One B-rep face of a CAD part: STEP entity #1838.
In plain terms, the planar face has unit normal (1, 0, 0).
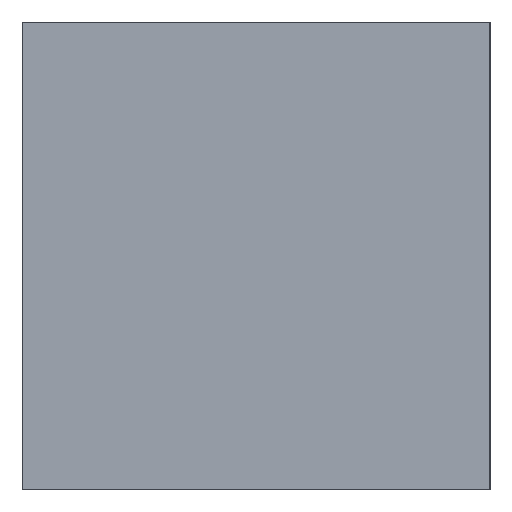
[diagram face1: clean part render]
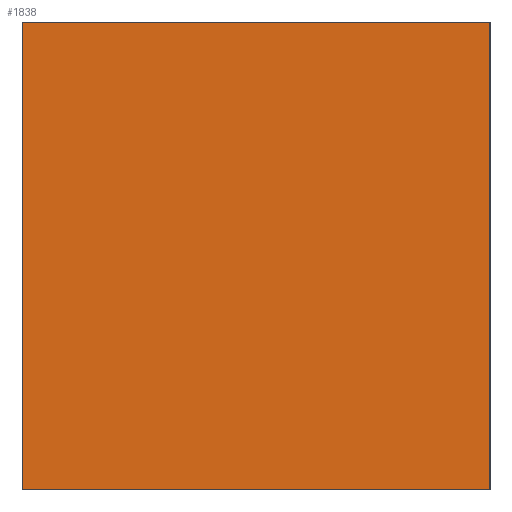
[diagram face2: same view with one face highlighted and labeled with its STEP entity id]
Its self-contained STEP definition (entity closure, numbers rounded to 3 decimals):
#1799=CARTESIAN_POINT('Axis2P3D Location',(-150.,0.,0.)) ;
#1804=CARTESIAN_POINT('Line Origine',(-150.,0.,-20.)) ;
#1808=CARTESIAN_POINT('Vertex',(-150.,-10.,-20.)) ;
#1810=CARTESIAN_POINT('Vertex',(-150.,10.,-20.)) ;
#1813=CARTESIAN_POINT('Line Origine',(-150.,10.,-10.)) ;
#1817=CARTESIAN_POINT('Vertex',(-150.,10.,0.)) ;
#1820=CARTESIAN_POINT('Line Origine',(-150.,0.,0.)) ;
#1824=CARTESIAN_POINT('Vertex',(-150.,-10.,0.)) ;
#1827=CARTESIAN_POINT('Line Origine',(-150.,-10.,-10.)) ;
#1800=DIRECTION('Axis2P3D Direction',(1.,0.,0.)) ;
#1801=DIRECTION('Axis2P3D XDirection',(0.,1.,0.)) ;
#1805=DIRECTION('Vector Direction',(0.,1.,0.)) ;
#1814=DIRECTION('Vector Direction',(0.,0.,1.)) ;
#1821=DIRECTION('Vector Direction',(0.,-1.,0.)) ;
#1828=DIRECTION('Vector Direction',(0.,0.,-1.)) ;
#1802=AXIS2_PLACEMENT_3D('Plane Axis2P3D',#1799,#1800,#1801) ;
#1833=ORIENTED_EDGE('',*,*,#1812,.T.) ;
#1834=ORIENTED_EDGE('',*,*,#1819,.T.) ;
#1835=ORIENTED_EDGE('',*,*,#1826,.T.) ;
#1836=ORIENTED_EDGE('',*,*,#1831,.T.) ;
#1806=VECTOR('Line Direction',#1805,1.) ;
#1815=VECTOR('Line Direction',#1814,1.) ;
#1822=VECTOR('Line Direction',#1821,1.) ;
#1829=VECTOR('Line Direction',#1828,1.) ;
#1838=ADVANCED_FACE('MANIFOLD_SOLID_BREP #7846',(#1837),#1803,.T.) ;
#1812=EDGE_CURVE('',#1809,#1811,#1807,.T.) ;
#1819=EDGE_CURVE('',#1811,#1818,#1816,.T.) ;
#1826=EDGE_CURVE('',#1818,#1825,#1823,.T.) ;
#1831=EDGE_CURVE('',#1825,#1809,#1830,.T.) ;
#1832=EDGE_LOOP('',(#1833,#1834,#1835,#1836)) ;
#1837=FACE_OUTER_BOUND('',#1832,.T.) ;
#1807=LINE('Line',#1804,#1806) ;
#1816=LINE('Line',#1813,#1815) ;
#1823=LINE('Line',#1820,#1822) ;
#1830=LINE('Line',#1827,#1829) ;
#1803=PLANE('Plane',#1802) ;
#1809=VERTEX_POINT('',#1808) ;
#1811=VERTEX_POINT('',#1810) ;
#1818=VERTEX_POINT('',#1817) ;
#1825=VERTEX_POINT('',#1824) ;
